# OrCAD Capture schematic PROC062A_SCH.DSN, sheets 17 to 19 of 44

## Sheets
17 16. DDR4 ECC & TERMINATIONS: size C; title: DDR4 ECC & TERMINATIONS
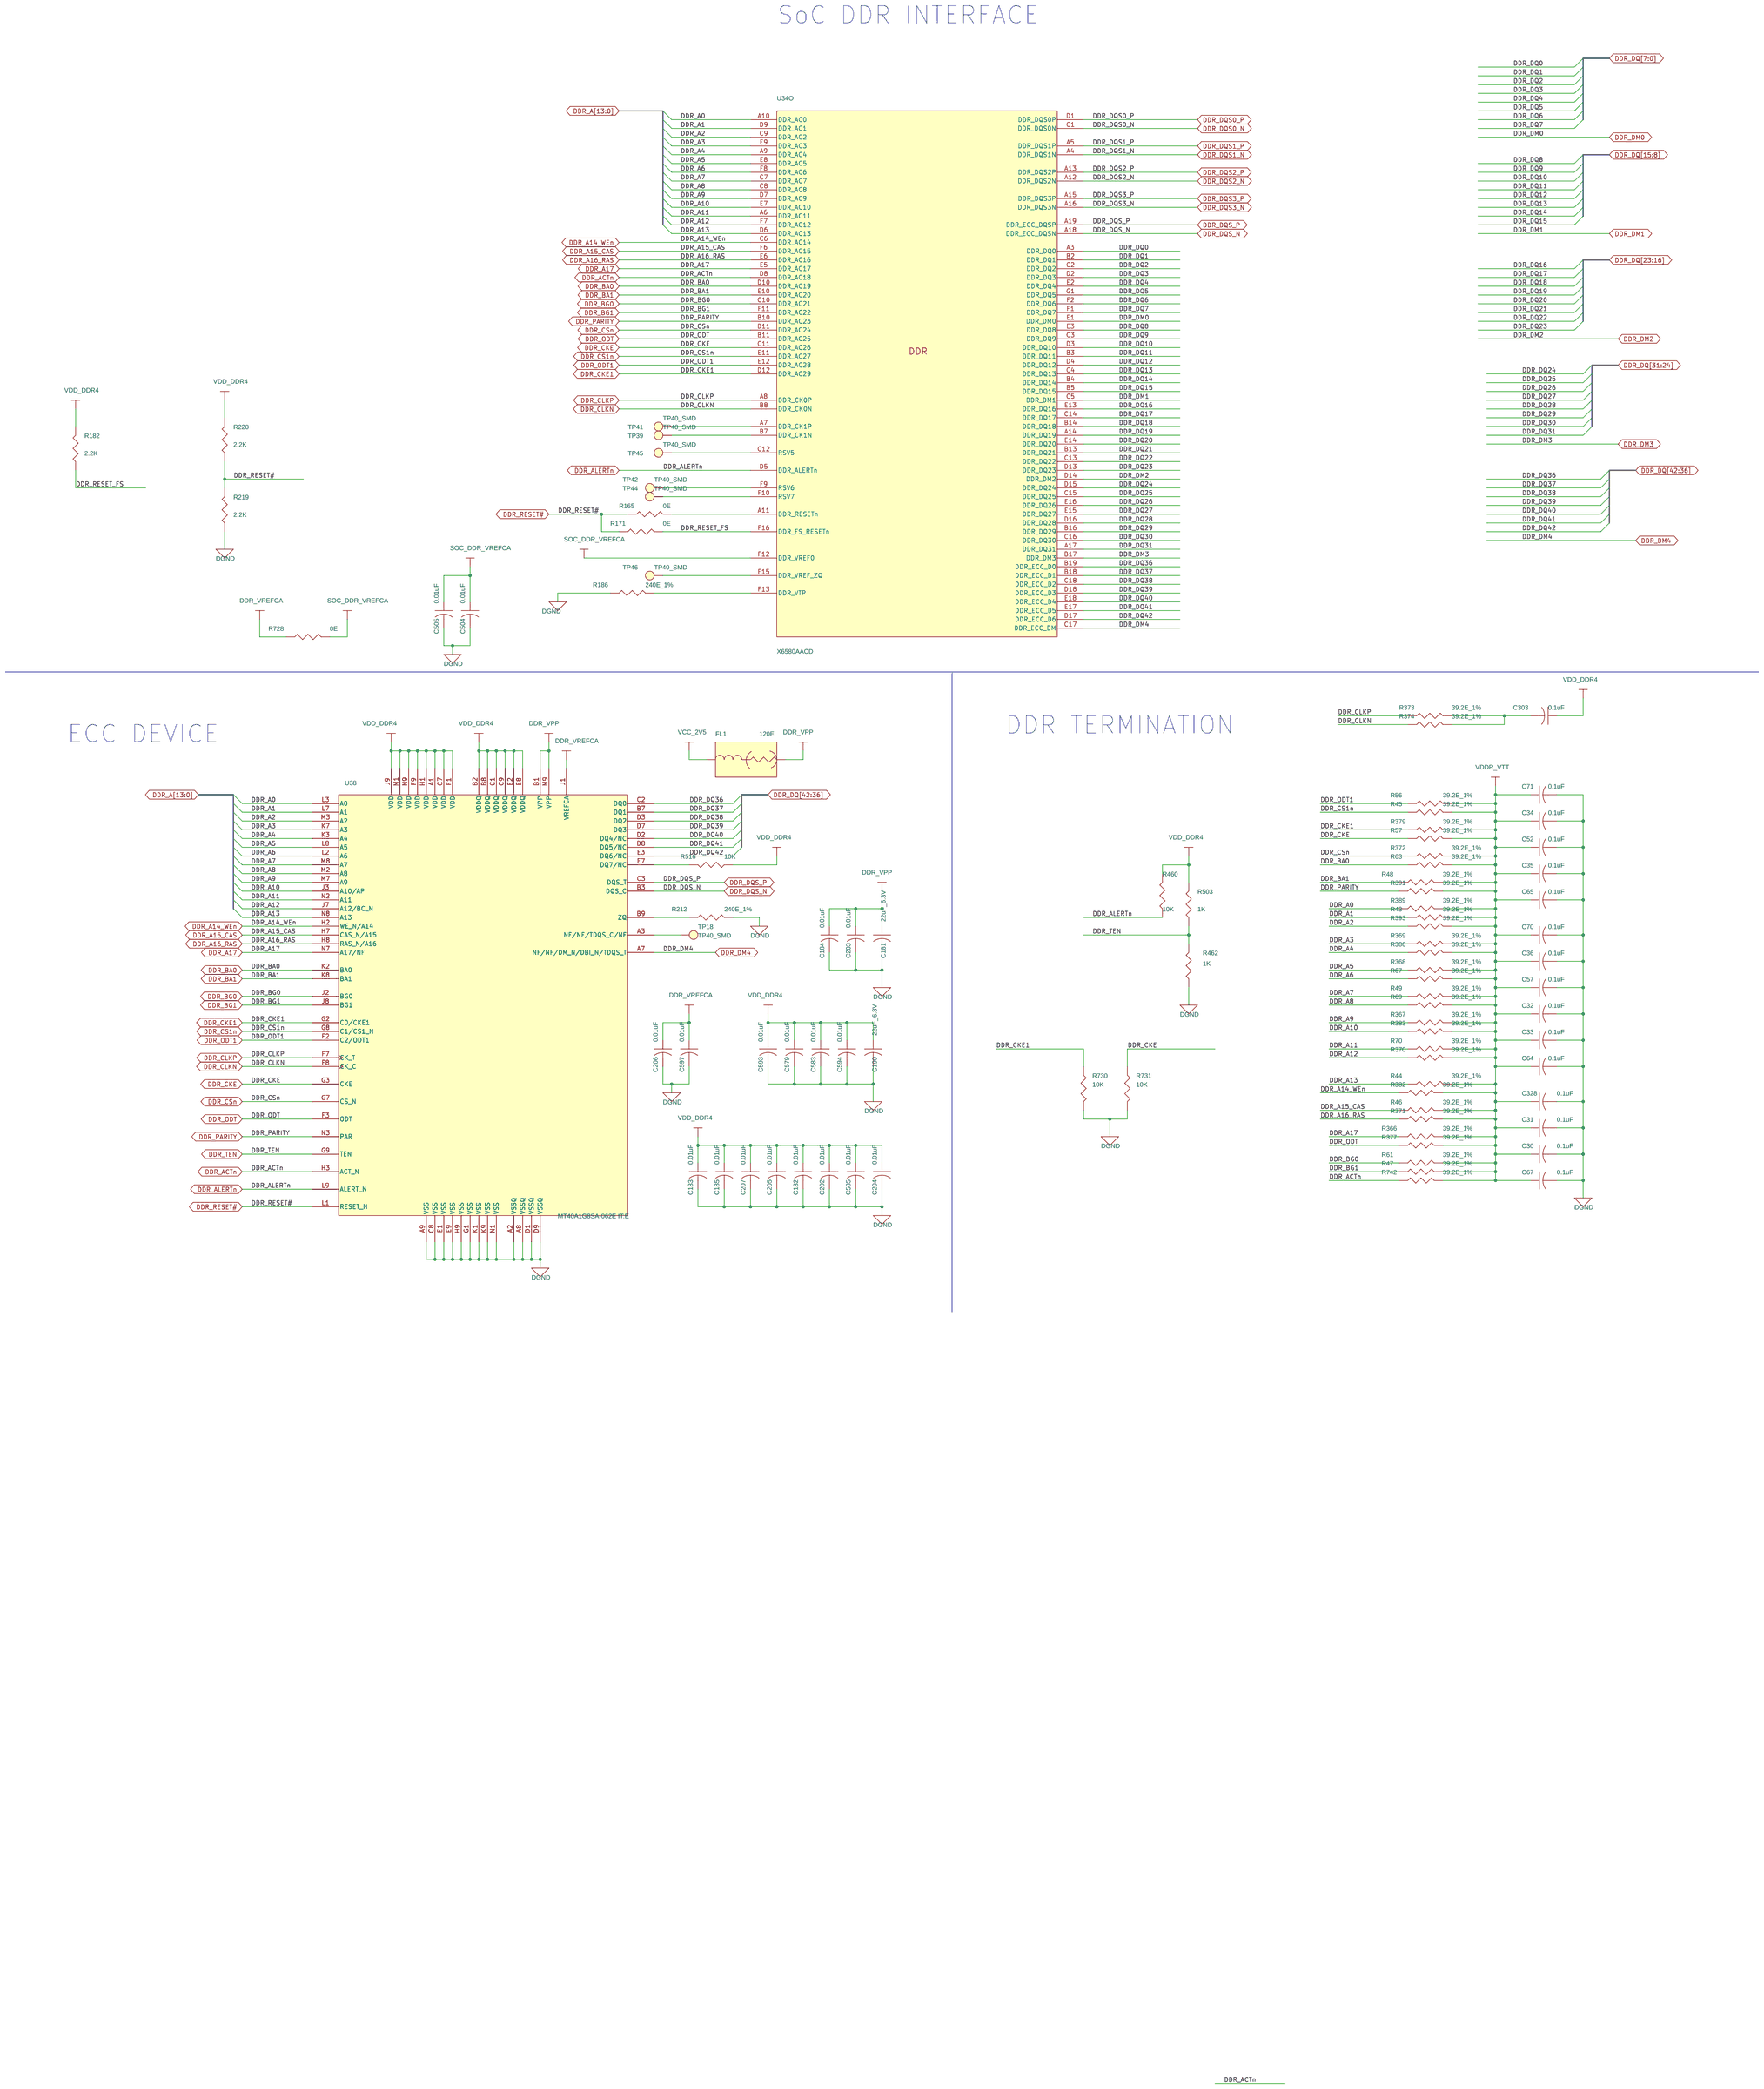
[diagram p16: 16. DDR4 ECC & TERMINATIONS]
18 17. eMMC FLASH: size C; title: eMMC FLASH_SDCARD INTERFACE
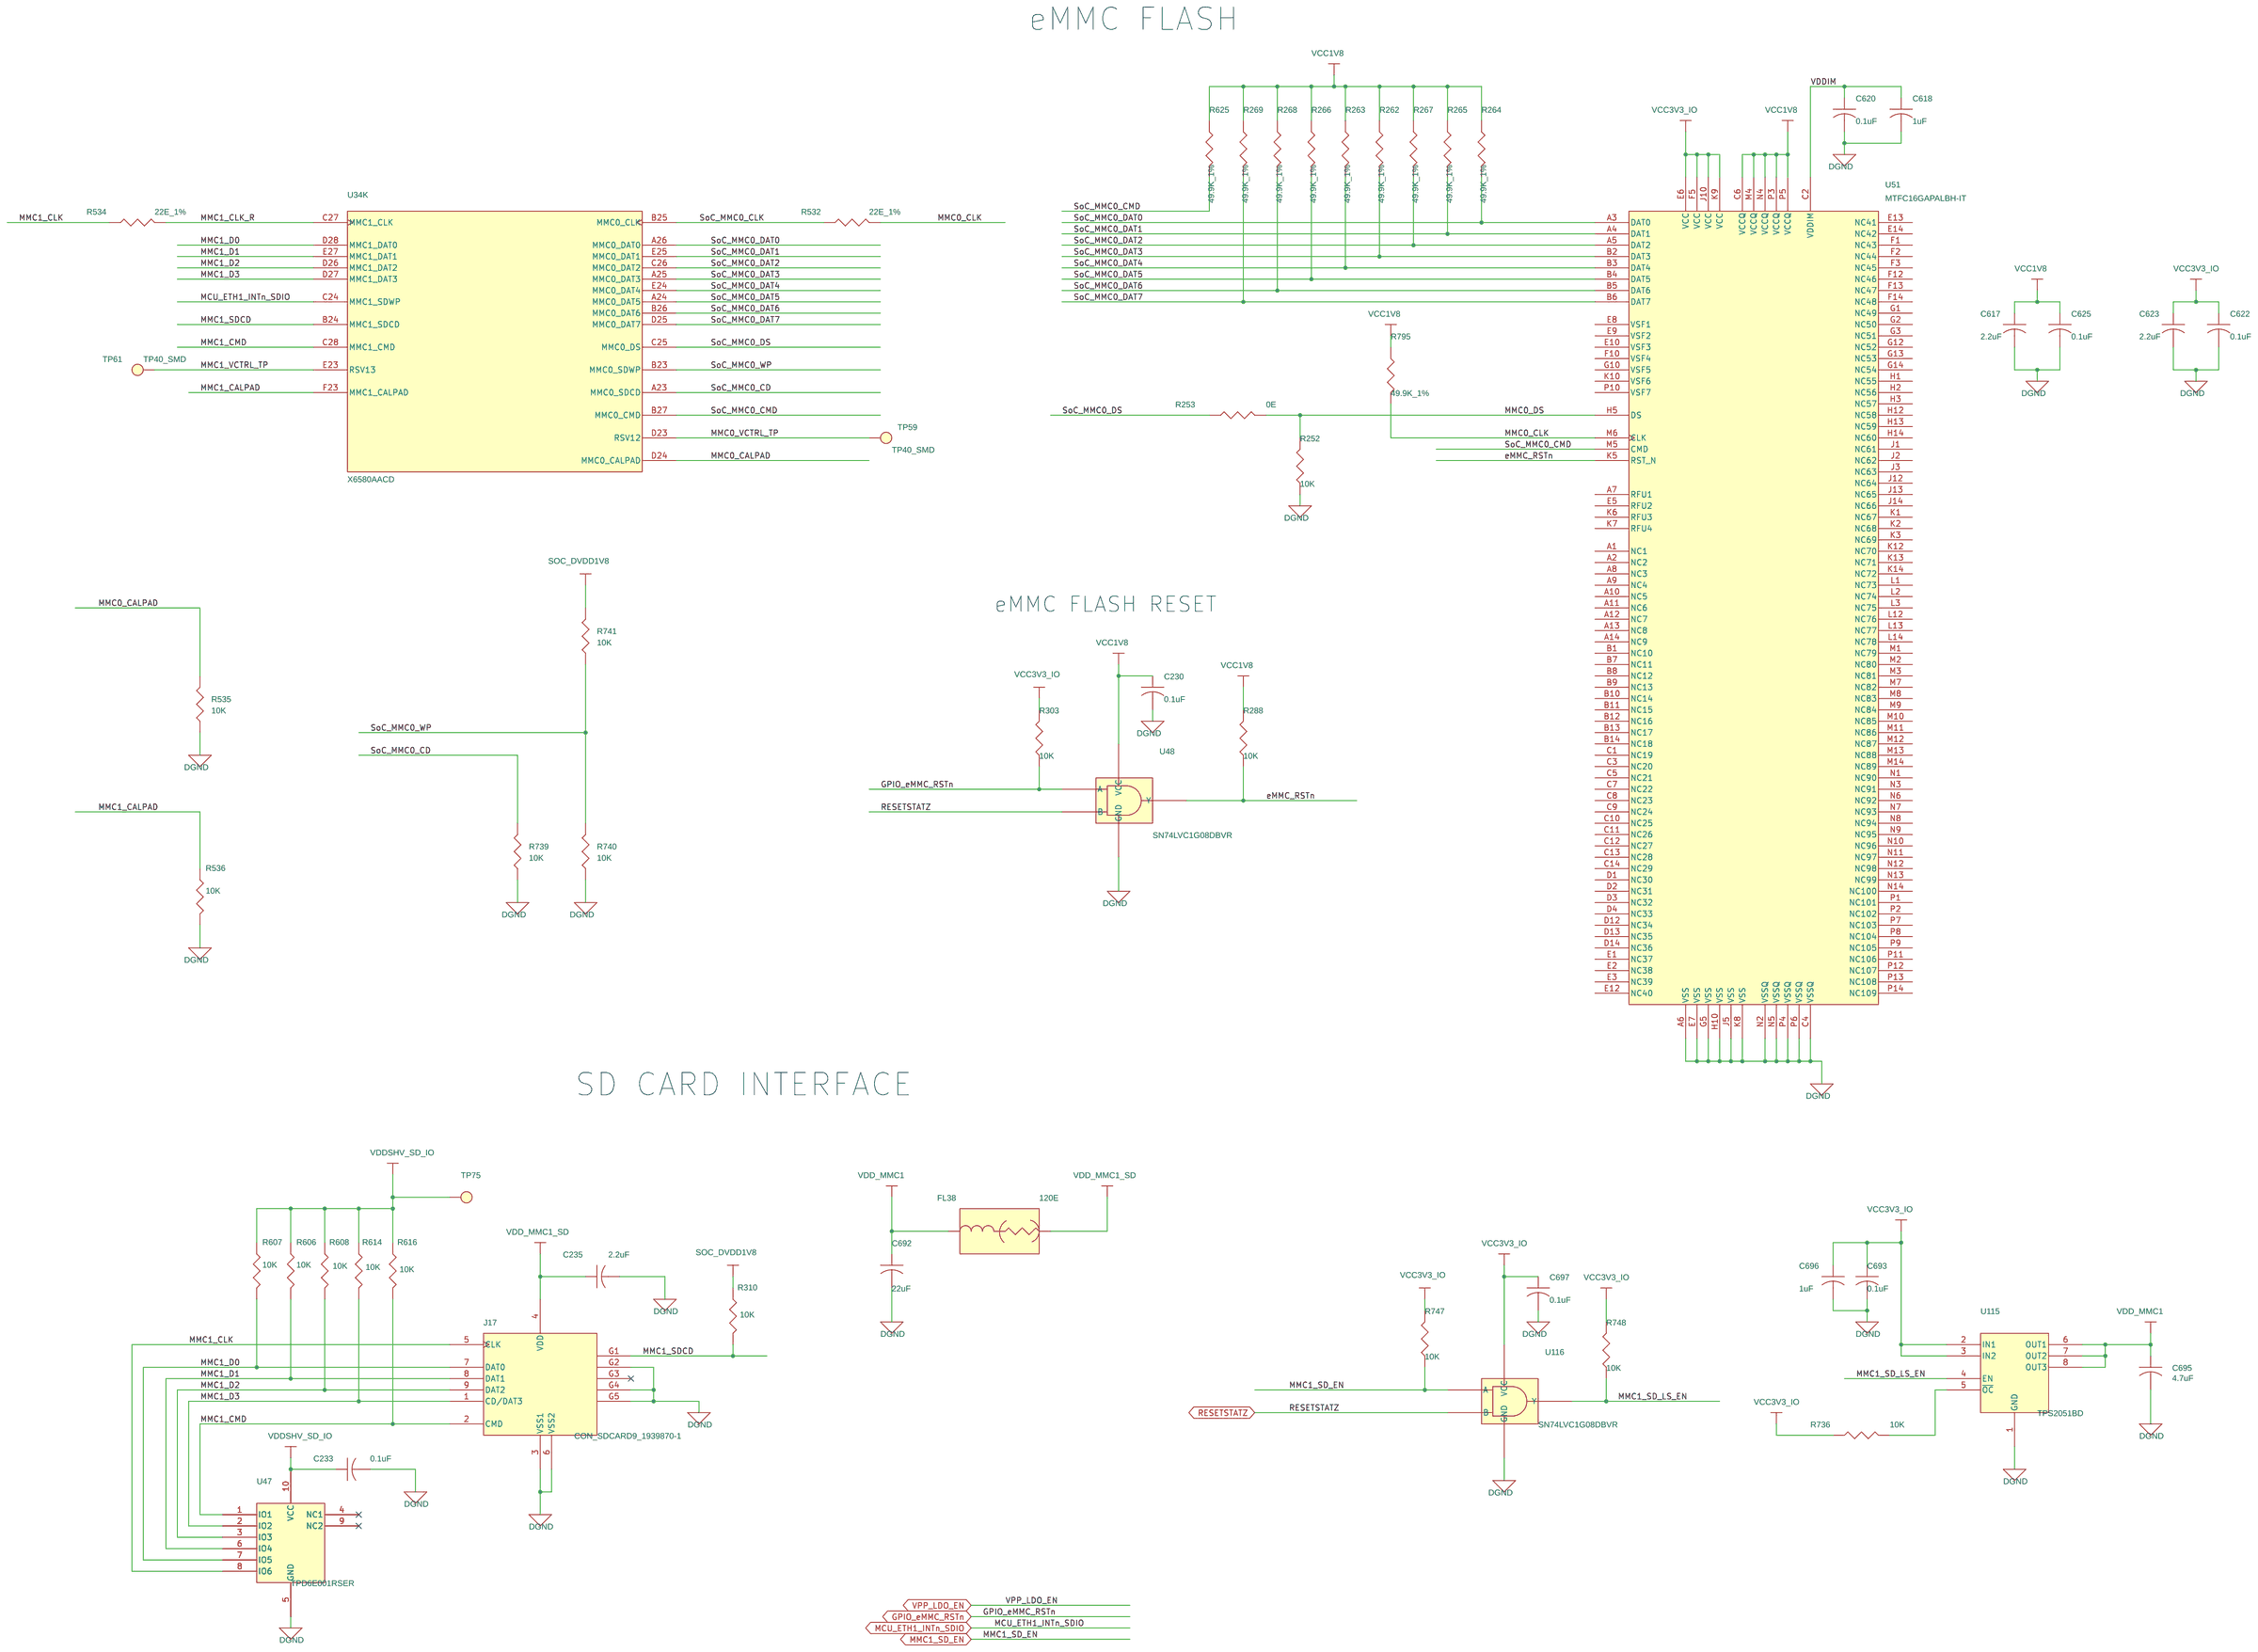
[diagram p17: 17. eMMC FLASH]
19 18. OSPI FLASH & SPI NOR FLASH: size C; title: OSPI FLASH & SPI NOR FLASH

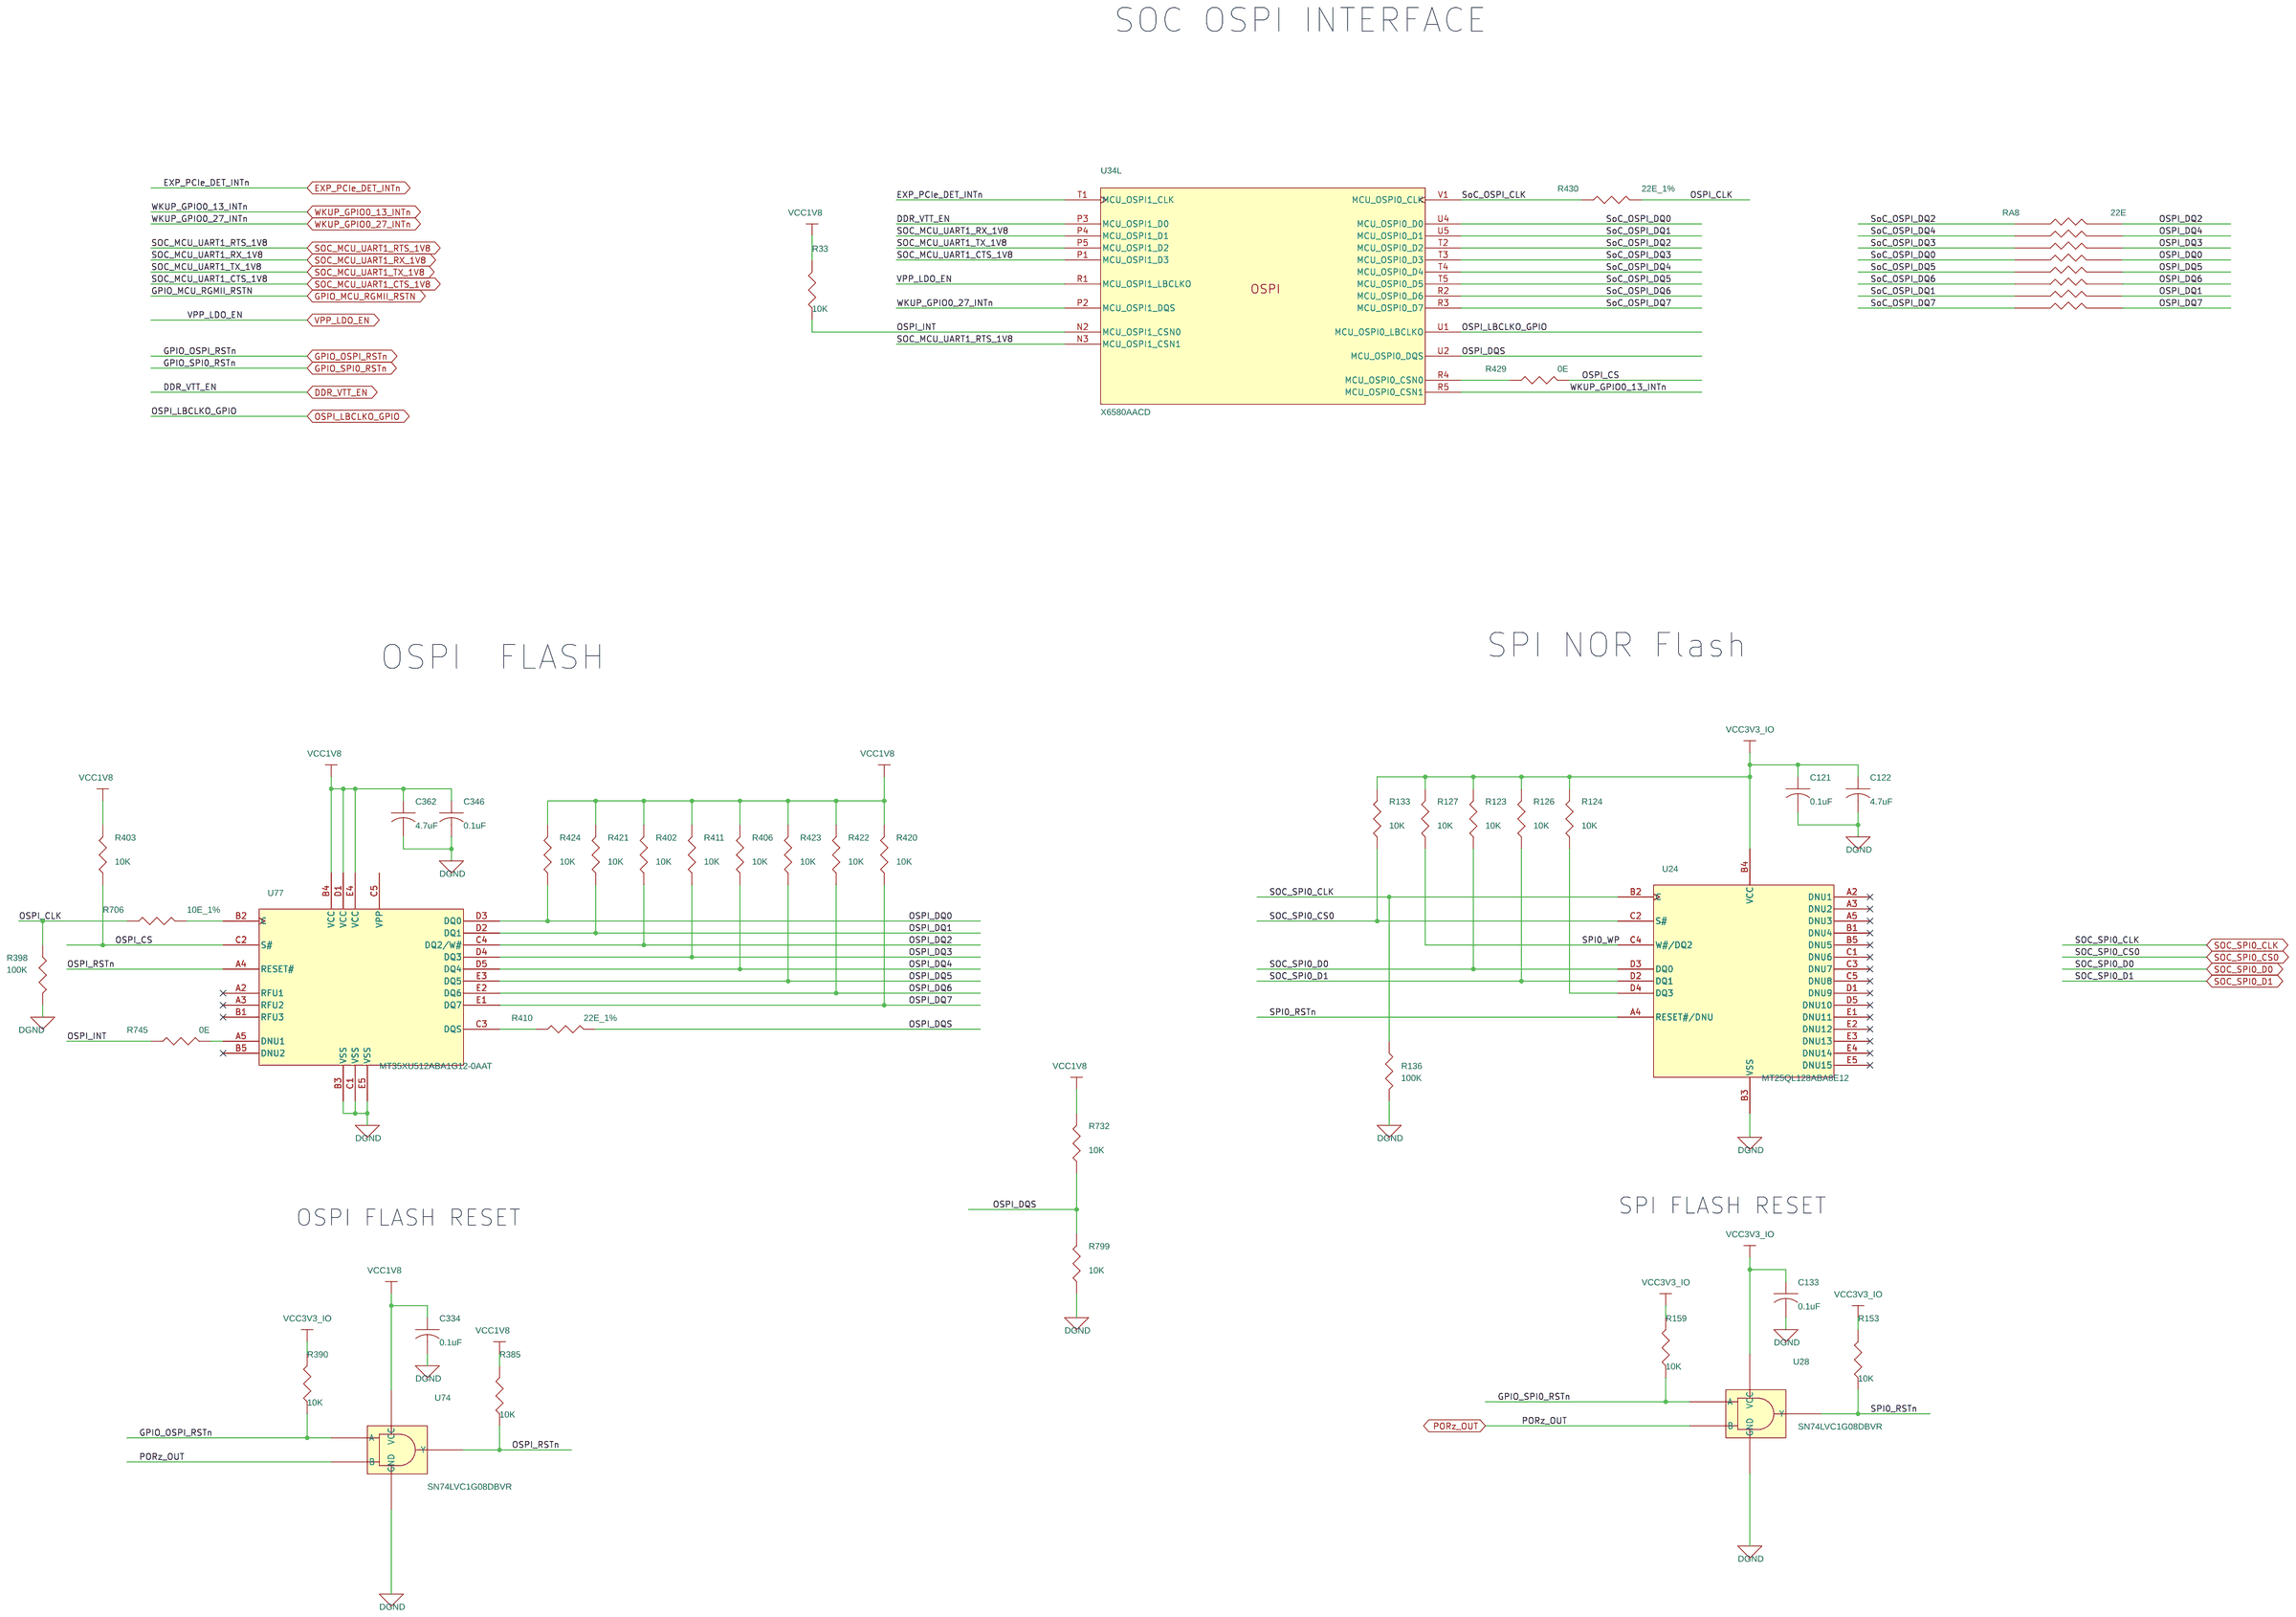
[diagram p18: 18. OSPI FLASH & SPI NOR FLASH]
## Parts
sheet 16. DDR4 ECC & TERMINATIONS
C30  0.1uF  [CAP0201_0-5]
C31  0.1uF  [CAP0201_0-5]
C32  0.1uF  [CAP0201_0-5]
C33  0.1uF  [CAP0201_0-5]
C34  0.1uF  [CAP0201_0-5]
C35  0.1uF  [CAP0201_0-5]
C36  0.1uF  [CAP0201_0-5]
C52  0.1uF  [CAP0201_0-5]
C57  0.1uF  [CAP0201_0-5]
C64  0.1uF  [CAP0201_0-5]
C65  0.1uF  [CAP0201_0-5]
C67  0.1uF  [CAP0201_0-5]
C70  0.1uF  [CAP0201_0-5]
C71  0.1uF  [CAP0201_0-5]
C181  22uF_6.3V  [CAP0603]
C182  0.01uF  [CAP0201_0-5]
C183  0.01uF  [CAP0201_0-5]
C184  0.01uF  [CAP0201_0-5]
C185  0.01uF  [CAP0201_0-5]
C190  22uF_6.3V  [CAP0603]
C202  0.01uF  [CAP0201_0-5]
C203  0.01uF  [CAP0201_0-5]
C204  0.01uF  [CAP0201_0-5]
C205  0.01uF  [CAP0201_0-5]
C206  0.01uF  [CAP0201_0-5]
C207  0.01uF  [CAP0201_0-5]
C303  0.1uF  [CAP0201_0-5]
C328  0.1uF  [CAP0201_0-5]
C504  0.01uF  [CAP0201_0-5]
C505  0.01uF  [CAP0201_0-5]
C579  0.01uF  [CAP0201_0-5]
C583  0.01uF  [CAP0201_0-5]
C585  0.01uF  [CAP0201_0-5]
C593  0.01uF  [CAP0201_0-5]
C594  0.01uF  [CAP0201_0-5]
C597  0.01uF  [CAP0201_0-5]
FL1  120E  [EMIFIL_BLM15A_0402_0-6]
R43  39.2E_1%  [RES0402]
R44  39.2E_1%  [RES0402]
R45  39.2E_1%  [RES0402]
R46  39.2E_1%  [RES0402]
R47  39.2E_1%  [RES0402]
R48  39.2E_1%  [RES0402]
R49  39.2E_1%  [RES0402]
R56  39.2E_1%  [RES0402]
R57  39.2E_1%  [RES0402]
R61  39.2E_1%  [RES0402]
R63  39.2E_1%  [RES0402]
R67  39.2E_1%  [RES0402]
R69  39.2E_1%  [RES0402]
R70  39.2E_1%  [RES0402]
R165  0E  [RES0402_0-5]
R171  0E  [RES0402_0-5]
R182  2.2K  [RES0402_0-5]
R186  240E_1%  [RES0402]
R212  240E_1%  [RES0402]
R219  2.2K  [RES0402_0-5]
R220  2.2K  [RES0402_0-5]
R366  39.2E_1%  [RES0402]
R367  39.2E_1%  [RES0402]
R368  39.2E_1%  [RES0402]
R369  39.2E_1%  [RES0402]
R370  39.2E_1%  [RES0402]
R371  39.2E_1%  [RES0402]
R372  39.2E_1%  [RES0402]
R373  39.2E_1%  [RES0402]
R374  39.2E_1%  [RES0402]
R377  39.2E_1%  [RES0402]
R379  39.2E_1%  [RES0402]
R382  39.2E_1%  [RES0402]
R383  39.2E_1%  [RES0402]
R386  39.2E_1%  [RES0402]
R389  39.2E_1%  [RES0402]
R391  39.2E_1%  [RES0402]
R393  39.2E_1%  [RES0402]
R460  10K  [RES0402_0-5]
R462  1K  [RES0201]
R503  1K  [RES0201]
R516  10K  [RES0402_0-5]
R728  0E  [RES0402_0-5]
R730  10K  [RES0402_0-5]
R731  10K  [RES0402_0-5]
R742  39.2E_1%  [RES0402]
TP18  TP40_SMD  [TP40_SMD]
TP39  TP40_SMD  [TP40_SMD]
TP41  TP40_SMD  [TP40_SMD]
TP42  TP40_SMD  [TP40_SMD]
TP44  TP40_SMD  [TP40_SMD]
TP45  TP40_SMD  [TP40_SMD]
TP46  TP40_SMD  [TP40_SMD]
U38  MT40A1G8SA-062E IT:E  [FBGA78_31-49_300X440_1-2]
sheet 17. eMMC FLASH
C230  0.1uF  [CAP0201_0-5]
C233  0.1uF  [CAP0201_0-5]
C235  2.2uF  [CAP0402_0-75]
C617  2.2uF  [CAP0402_0-75]
C618  1uF  [CAP0402_0-75]
C620  0.1uF  [CAP0201_0-5]
C622  0.1uF  [CAP0201_0-5]
C623  2.2uF  [CAP0402_0-75]
C625  0.1uF  [CAP0201_0-5]
C692  22uF  [CAP1206_2]
C693  0.1uF  [CAP0201_0-5]
C695  4.7uF  [CAP0402_0-75]
C696  1uF  [CAP0402_0-75]
C697  0.1uF  [CAP0201_0-5]
FL38  120E  [EMIFIL_BLM15A_0402_0-6]
J17  CON_SDCARD9_1939870-1  [CON_SD9_1939870-1_S_R_S_2-9]
R252  10K  [RES0402_0-5]
R253  0E  [RES0402_0-5]
R262  49.9K_1%  [RES0402]
R263  49.9K_1%  [RES0402]
R264  49.9K_1%  [RES0402]
R265  49.9K_1%  [RES0402]
R266  49.9K_1%  [RES0402]
R267  49.9K_1%  [RES0402]
R268  49.9K_1%  [RES0402]
R269  49.9K_1%  [RES0402]
R288  10K  [RES0402_0-5]
R303  10K  [RES0402_0-5]
R310  10K  [RES0402_0-5]
R532  22E_1%  [RES0402]
R534  22E_1%  [RES0402]
R535  10K  [RES0402_0-5]
R536  10K  [RES0402_0-5]
R606  10K  [RES0402_0-5]
R607  10K  [RES0402_0-5]
R608  10K  [RES0402_0-5]
R614  10K  [RES0402_0-5]
R616  10K  [RES0402_0-5]
R625  49.9K_1%  [RES0402]
R736  10K  [RES0402_0-5]
R739  10K  [RES0402_0-5]
R740  10K  [RES0402_0-5]
R741  10K  [RES0402_0-5]
R747  10K  [RES0402_0-5]
R748  10K  [RES0402_0-5]
R795  49.9K_1%  [RES0402]
TP59  TP40_SMD  [TP40_SMD]
TP61  TP40_SMD  [TP40_SMD]
TP75  TP40_SMD  [TP40_SMD]
U47  TPD6E001RSER  [UQFN10_19-68_80X60_0-6]
U48  SN74LVC1G08DBVR  [SOT23-5]
U51  MTFC16GAPALBH-IT  [VFBGA153_19-68_460X520_1-1]
U115  TPS2051BD  [SOIC8_1-8]
U116  SN74LVC1G08DBVR  [SOT23-5]
sheet 18. OSPI FLASH & SPI NOR FLASH
C121  0.1uF  [CAP0201_0-5]
C122  4.7uF  [CAP0402_0-75]
C133  0.1uF  [CAP0201_0-5]
C334  0.1uF  [CAP0201_0-5]
C346  0.1uF  [CAP0201_0-5]
C362  4.7uF  [CAP0402_0-75]
R33  10K  [RES0402_0-5]
R123  10K  [RES0402_0-5]
R124  10K  [RES0402_0-5]
R126  10K  [RES0402_0-5]
R127  10K  [RES0402_0-5]
R133  10K  [RES0402_0-5]
R136  100K  [RES0402_0-5]
R153  10K  [RES0402_0-5]
R159  10K  [RES0402_0-5]
R385  10K  [RES0402_0-5]
R390  10K  [RES0402_0-5]
R398  100K  [RES0402_0-5]
R402  10K  [RES0402_0-5]
R403  10K  [RES0402_0-5]
R406  10K  [RES0402_0-5]
R410  22E_1%  [RES0402]
R411  10K  [RES0402_0-5]
R420  10K  [RES0402_0-5]
R421  10K  [RES0402_0-5]
R422  10K  [RES0402_0-5]
R423  10K  [RES0402_0-5]
R424  10K  [RES0402_0-5]
R429  0E  [RES0402_0-5]
R430  22E_1%  [RES0402]
R706  10E_1%  [RES0402_0-5]
R732  10K  [RES0402_0-5]
R745  0E  [RES0402_0-5]
R799  10K  [RES0402_0-5]
RA8  22E  [RESA_0402-8]
U24  MT25QL128ABA8E12  [TPBGA24_39-37_240X320_1-2]
U28  SN74LVC1G08DBVR  [SOT23-5]
U74  SN74LVC1G08DBVR  [SOT23-5]
U77  MT35XU512ABA1G12-0AAT  [TPBGA24_39-37_240X320_1-2]
sheet 29. USB2.0_INTERFACE
U34  X6580AACD  [BGA784_31-49_910X910_1-7]  (sections A,B,C,D,E,F,G,H,I,J,K,L,M,N,O,P,Q,R,S)

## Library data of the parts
C30-C36 C52 C57 C64 C65 C67 C70 C71 C121 C133 C230 C233 C303 C328 C334 C346 C620 C622 C625 C693 C697 = CAP: CAP CERAMIC 0.1uF 16V 10% X5R 0201; Chkd/date: MANIRAJA/120218; Crtd /date: MANIRAJA/120218; Custom_Duty: 15%; Customs_HS_Code: 85322990; Distributor_name: DIGIKEY; Distributor_part_number: 490-16742-1-ND; Height: 0.33MM; Mfr_name: MURATA; Mfr_part_number: GRM033R61C104KE84J; Mistral Part No: 120009030072-R; Package: 0201; Part_type: CAPACITORS\CERAMIC; Project: TI_MAXIE_CPB; RoHS: RoHS; Temperature: -55°C+85°C; Tolerance: 10%; Voltage: 16V; Wattage: NA; Weight: 0.33mg; Datasheet: Y:\MIS_DATABASE\DATASHEETS\CAPACITORS\GRM033R61C104KE84.PDF
C181 C190 = CAP: CAP CERAMIC 22uF 6.3V 20% X5R 0603; Alternate_mfr_name_A: YAGEO AMERICA; Alternate_mfr_part_number_A: CC0603MRX5R5BB226; Chkd/date: JEBRAN/090915; Crtd /date: JEBRAN/090915; Custom_Duty: 15%; Customs_HS_Code: 85322990; Distributor_name: DIGIKEY; Distributor_name_A: DIGIKEY; Distributor_part_number: 490-7611-2-ND; Distributor_part_number_A: 311-1815-1-ND; Height: 1.00MM; Mfr_name: MURATA; Mfr_part_number: GRM188R60J226MEA0; Mistral Part No: 120015090007-R; Package: 0603; Part_type: CAPACITORS\CERAMIC; Project: OCTBTS_3000; RoHS: RoHS; Temperature: -55°C+85°C; Tolerance: 20%; Voltage: 6.3V; Wattage: NA; Weight: NA; Datasheet: Y:\MIS_DATABASE\DATASHEETS\CAPACITORS\GRM188SERIES.PDF
C182-C185 C202-C207 C504 C505 C579 C583 C585 C593 C594 C597 = CAP: CAP CERAMIC 0.01uF 25V 10% X5R 0201; Chkd/date: MANIRAJA/230118; Crtd /date: MANIRAJA/230118; Custom_Duty: 15%; Customs_HS_Code: 85322990; Distributor_name: DIGIKEY; Distributor_part_number: GRM033R61E103KA12J-ND; Height: 0.33MM; Mfr_name: MURATA; Mfr_part_number: GRM033R61E103KA12J; Mistral Part No: 120018010007-R; Package: 0201; Part_type: CAPACITORS\CERAMIC; Project: TI_MAXIE_CPB; RoHS: RoHS; Temperature: -55°C+85°C; Tolerance: 10%; Voltage: 25V; Wattage: NA; Weight: 0.33mg; Datasheet: Y:\MIS_DATABASE\DATASHEETS\CAPACITORS\GRM033R61E103KA12.PDF
FL1 FL38 = EMIFILTER_IND: FERRITE CHIP 120E 1.3A 0402; Chkd/date: VASANTHA/010117; Crtd /date: CHAITHANYA/150312; Custom_Duty: 24%; Customs_HS_Code: 85437099; Distributor_name: DIGIKEY; Distributor_part_number: 490-5203-1-ND; Footprint Path: Y:\MIS_DATABASE\Library\ALTIUM_TOOL\PCB_FOOTPRINTS\Altium_Footprint_Lib.PcbLib; Height: 0.55MM; Library Path: Y:\MIS_DATABASE\Library\ALTIUM_TOOL\SCHEMATICS_PARTS\MS_FILTER_Library.schlib; Mfr_name: MURATA; Mfr_part_number: BLM15PD121SN1; Mistral Part No: 130012030043-R; Package: 0402; Part_type: MISC\FILTER; Project: GEN_3-8; RoHS: RoHS; Temperature: -55°C+125°C; Tolerance: 25%; Voltage: NA; Wattage: NA; Weight: 0.65mg; Datasheet: Y:\MIS_DATABASE\DATASHEETS\DISCRETES\INDUCTORS\BLM18K-SERIES.PDF
R43-R49 R56 R57 R61 R63 R67 R69 R70 R366-R374 R377 R379 R382 R383 R386 R389 R391 R393 R742 = RESISTOR: RES 39.2E 1/16W 1% 0402; Chkd/date: RAGESH/210411; Crtd /date: MAZHAR/210411; Custom_Duty: 15%; Customs_HS_Code: 85332119; Distributor_name: DIGIKEY; Distributor_part_number: RMCF0402FT39R2CT-ND; Height: 0.40MM; Mfr_name: STACKPOLE ELECTRONICS; Mfr_part_number: RMCF0402FT39R2; Mistral Part No: 110011040030-R; Package: 0402; Part_type: RESISTORS\FIXED; Project: AOD_POD-BASECARD; RoHS: RoHS; Temperature: -55°C+155°C; Tolerance: 1%; Voltage: NA; Wattage: 1/16W; Weight: NA; Datasheet: Y:\MIS_DATABASE\DATASHEETS\RESISTORS\RMCF-SERIES.PDF
R165 R171 R253 R429 R728 R745 = RESISTOR: RES 0E 1/16W 0402; Chkd/date: VASANTHA/201216; Crtd /date: MUDDU/190810; Custom_Duty: 15%; Customs_HS_Code: 85332119; Distributor_name: DIGIKEY; Distributor_part_number: 541-0.0JCT-ND; Footprint Path: Y:\MIS_DATABASE\Library\ALTIUM_TOOL\PCB_FOOTPRINTS\Altium_Footprint_Lib.PcbLib; Height: 0.40MM; Library Path: Y:\MIS_DATABASE\Library\ALTIUM_TOOL\SCHEMATICS_PARTS\MS_DISCRETE_Library.schlib; Mfr_name: VISHAY; Mfr_part_number: CRCW04020000Z0ED; Mistral Part No: 110010080019-P; Package: 0402; Part_type: RESISTORS\FIXED; Project: PB_BUGBASE; RoHS: Pb-Free; Temperature: -55°C+155°C; Tolerance: NA; Voltage: NA; Wattage: 1/16W; Weight: 0.65g/1000pcs; Datasheet: Y:\MIS_DATABASE\DATASHEETS\RESISTORS\CRCW0603.PDF
R182 R219 R220 = RESISTOR: RES 2.2K 1/16W 5% 0402; Chkd/date: VASANTHA/061216; Crtd /date: BAVISH/021210; Custom_Duty: 15%; Customs_HS_Code: 85332119; Distributor_name: DIGIKEY; Distributor_part_number: 311-2.2KJRCT-ND; Footprint Path: VALUE IS VAILABLE 3 TIMES; Height: 0.40MM; Mfr_name: YAGEO AMERICA; Mfr_part_number: RC0402JR-072K2L; Mistral Part No: 110010120018-R; Package: 0402; Part_type: RESISTORS\FIXED; Project: TE4; RoHS: RoHS; Temperature: -55°C+155°C; Tolerance: 5%; Voltage: NA; Wattage: 1/16W; Weight: 0.65mg; Datasheet: Y:\MIS_DATABASE\DATASHEETS\RESISTORS\YAGEO.PDF
R186 R212 = RESISTOR: RES 240E 1/10W 1% 0402; Chkd/date: MAZHAR/150611; Crtd /date: BAVISH/020611; Custom_Duty: 15%; Customs_HS_Code: 85332119; Distributor_name: DIGIKEY; Distributor_part_number: P240LCT-ND; Height: 0.40MM; Mfr_name: PANASONIC-ECG; Mfr_part_number: ERJ-2RKF2400X; Mistral Part No: 110011060017-R; Package: 0402; Part_type: RESISTORS\FIXED; Project: AM4515_EVM_LCD; RoHS: RoHS; Temperature: -55°C+125°C; Tolerance: 1%; Voltage: NA; Wattage: 1/10W; Weight: 0.8/1000g; Datasheet: Y:\MIS_DATABASE\DATASHEETS\RESISTORS\ERJ-2R.PDF
R33 R123 R124 R126 R127 R133 R153 R159 R252 R288 R303 R310 R385 R390 R402 R403 R406 R411 R420-R424 R460 R516 R535 R536 R606-R608 R614 R616 R730-R732 R736 R739-R741 R747 R748 R799 = RESISTOR: RES 10K 1/16W 5% 0402; Chkd/date: VASANTHA/061216; Crtd /date: MAZHAR/230805; Custom_Duty: 15%; Customs_HS_Code: 85332119; Distributor_name: DIGIKEY; Distributor_part_number: 311-10KJRCT-ND; Footprint Path: Y:\MIS_DATABASE\Library\ALTIUM_TOOL\PCB_FOOTPRINTS\Altium_Footprint_Lib.PcbLib; Height: 0.40MM; Library Path: Y:\MIS_DATABASE\Library\ALTIUM_TOOL\SCHEMATICS_PARTS\MS_DISCRETE_Library.schlib; Mfr_name: YAGEO AMERICA; Mfr_part_number: RC0402JR-0710KL; Mistral Part No: 110009030208-R; Package: 0402; Part_type: RESISTORS\FIXED; Project: HSE; RoHS: Pb-Free; Temperature: -55°C+155°C; Tolerance: 5%; Voltage: NA; Wattage: 1/16W; Weight: 0.65mg; Datasheet: Y:\MIS_DATABASE\DATASHEETS\RESISTORS\YAGEO-RC0402.PDF
R462 R503 = RESISTOR: RES 1K 1/20W 5% 0201; Chkd/date: JEBRAN/110815; Crtd /date: JEBRAN/110815; Custom_Duty: 15%; Customs_HS_Code: 85332119; Distributor_name: DIGIKEY; Distributor_part_number: 541-1.00KAABCT-ND; Height: 0.28MM; Mfr_name: VISHAY; Mfr_part_number: CRCW02011K00FKED; Mistral Part No: 110015080014-R; Package: 0201; Part_type: RESISTORS\FIXED; Project: OCTASIC_3000; RoHS: RoHS; Temperature: -55°C+155°C; Tolerance: 5%; Voltage: NA; Wattage: 1/20W; Weight: NA; Datasheet: Y:\MIS_DATABASE\DATASHEETS\RESISTORS\CRCW0201.PDF
TP18 TP39 TP41 TP42 TP44-TP46 TP59 TP61 TP75 = TESTPOINT: TESTPOINT CIR 40 SMD; Chkd/date: MAZHAR/190505; Crtd /date: MAZHAR/190505; Distributor_name: NA; Distributor_part_number: NA; Footprint Path: Y:\MIS_DATABASE\Library\ALTIUM_TOOL\PCB_FOOTPRINTS\Altium_Footprint_Lib.PcbLib; Height: NA; Library Path: Y:\MIS_DATABASE\Library\ALTIUM_TOOL\SCHEMATICS_PARTS\MS_DISCRETE_Library.schlib; MECHANICAL 3D STEP FILE: NA; Mfr_name: LOCAL; Mistral Part No: 130009030933; Package: SMD; Project: RAINIER-3; RoHS: NA; Temperature: NA; Tolerance: NA; Voltage: NA; Wattage: NA; Weight: NA; Datasheet: NA
U38 = MT40A1G8WE-083_FBGA78: IC 1G8 DDR4 SDRAM MEMORY FBGA78; Chkd/date: MANIRAJA/010819; Crtd /date: ALVY/010819; Custom_Duty: 15%; Customs_HS_Code: 85423100; Distributor_name: DIGIKEY; Distributor_part_number: MT40A1G8SA-062EIT:E-ND; Footprint Path: Y:\MIS_DATABASE\Library\ALTIUM_TOOL\PCB_FOOTPRINTS\Altium_Footprint_Lib.PcbLib; Height: 1.20MM; Library Path: Y:\MIS_DATABASE\Library\ALTIUM_TOOL\SCHEMATICS_PARTS\MS_MISCMEMORY_Library.schlib; Mfr_name: MICRON; Mistral Part No: 141119080001-R; Package: FBGA78; Part_type: ICS\DIGITAL\MEMORY; Project: TI_MAXIE_CPB; RoHS: RoHS; Temperature: -40°C+95°C; Tolerance: NA; Voltage: NA; Wattage: NA; Weight: NA; Datasheet: Y:\MIS_DATABASE\DATASHEETS\ICS\MEMORY\MT40AXX.PDF
C235 C617 C623 = CAP: CAP CERAMIC 2.2uF 10V 20% X5R 0402; Chkd/date: MANIRAJA/240118; Crtd /date: MANIRAJA/240118; Custom_Duty: 15%; Customs_HS_Code: 85322990; Distributor_name: DIGIKEY; Distributor_part_number: 490-12254-1-ND; Height: 0.55MM; Mfr_name: MURATA; Mfr_part_number: GRT155R61A225ME01D; Mistral Part No: 120018010016-R; Package: 0402; Part_type: CAPACITORS\CERAMIC; Project: TI_MAXIE_CPB; RoHS: RoHS; Temperature: -55°C+85°C; Tolerance: 20%; Voltage: 10V; Wattage: NA; Weight: 0.65mg; Datasheet: Y:\MIS_DATABASE\DATASHEETS\CAPACITORS\GRT155R61A225ME01.PDF
C618 C696 = CAP: CAP CERAMIC 1uF 16V 20% X5R 0402; Chkd/date: MANIRAJA/150218; Crtd /date: ALVY/150218; Custom_Duty: 15%; Customs_HS_Code: 85322990; Distributor_name: DIGIKEY; Distributor_part_number: 587-5514-1-ND; Footprint Path: Y:\MIS_DATABASE\Library\ALTIUM_TOOL\PCB_FOOTPRINTS\Altium_Footprint_Lib.PcbLib; Height: 0.55MM; Library Path: Y:\MIS_DATABASE\Library\ALTIUM_TOOL\SCHEMATICS_PARTS\MS_DISCRETE_Library.schlib; Mfr_name: TAIYO YUDEN; Mfr_part_number: EMK105BJ105MV-F; Mistral Part No: 120018020006-R; Package: 0402; Part_type: CAPACITORS\CERAMIC; Project: TI_MAXIE_CPB; RoHS: RoHS; Temperature: -55°C+85°C; Tolerance: 20%; Voltage: 16V; Wattage: NA; Weight: 0.65mg; Datasheet: Y:\MIS_DATABASE\DATASHEETS\CAPACITORS\EMK105BJ105MV-F.PDF
C692 = CAP: CAP CERAMIC 22uF 16V 20% X7R 1206; Chkd/date: VASANTHA/170117; Crtd /date: VASANTHA/170117; Custom_Duty: 15%; Customs_HS_Code: 85322990; Distributor_name: DIGIKEY; Distributor_part_number: 587-4319-1-ND; Height: 1.90MM; Mfr_name: TAIYO YUDEN; Mfr_part_number: EMK316BB7226ML-T; Mistral Part No: 120017010003-R; Package: 1206; Part_type: CAPACITORS\CERAMIC; Project: TRMM_SMART-M_PS; RoHS: RoHS; Temperature: -55°C+125°C; Tolerance: 20%; Voltage: 16V; Wattage: NA; Weight: 16.2mg; Datasheet: Y:\MIS_DATABASE\DATASHEETS\CAPACITORS\EMK316BB7226ML.PDF
C122 C362 C695 = CAP: CAP CERAMIC 4.7uF 10V 20% X5R 0402; Chkd/date: MANIRAJA/230118; Crtd /date: MANIRAJA/230118; Custom_Duty: 15%; Customs_HS_Code: 85322990; Distributor_name: DIGIKEY; Distributor_part_number: 478-10791-1-ND; Height: 0.71MM; Mfr_name: AVX CORPORATION; Mfr_part_number: 0402ZD475MAT2A; Mistral Part No: 120012060002-R; Package: 0402; Part_type: CAPACITORS\CERAMIC; Project: TI_MAXIE_CPB; RoHS: RoHS; Temperature: -55°C+85°C; Tolerance: 20%; Voltage: 10V; Wattage: NA; Weight: 0.65mg; Datasheet: Y:\MIS_DATABASE\DATASHEETS\CAPACITORS\AVX_MLC.PDF
J17 = CON_SDCARD9_1939870-1: CON SD CARD PUSH-PUSH 9POS RT SMD; Chkd/date: MANIRAJA/051017; Crtd /date: MANIRAJA/051017; Custom_Duty: 24%; Customs_HS_Code: 85369090; Distributor_name: DIGIKEY; Distributor_part_number: A118090CT-ND; Height: 2.90MM; MECHANICAL 3D STEP FILE: CON_SD9_1939870-1_S_R_S_3-4; Mfr_name: TE CONNECTIVITY; Mfr_part_number: 1939870-1; Mistral Part No: 150017100004-R; Package: SMD; Part_type: CONNECTOR\MEMORY CARD; Project: TI_MAXIE_CPB; RoHS: RoHS; Temperature: NA; Tolerance: NA; Voltage: NA; Wattage: NA; Weight: NA; Datasheet: Y:\MIS_DATABASE\DATASHEETS\CONNECTORS\1939870-XX.PDF
R262-R269 R625 R795 = RESISTOR: RES 49.9K1/16W 1% 0402; Chkd/date: MAZHAR/220709; Crtd /date: GEETHA/090606; Custom_Duty: 15%; Customs_HS_Code: 85332119; Distributor_name: DIGIKEY; Distributor_part_number: 311-49.9KLRCT-ND; Height: 0.40MM; Mfr_name: YAGEO AMERICA; Mfr_part_number: RC0402FR-0749K9L; Mistral Part No: 110009030904-P; Package: 0402; Part_type: RESISTORS\FIXED; Project: PNAV; RoHS: Pb-Free; Tolerance: 1%; Wattage: 1/16W; Datasheet: Y:\MIS_DATABASE\DATASHEETS\RESISTORS\YAGEO-RC0402.PDF
R410 R430 R532 = RESISTOR: RES 22E 1/16W 1% 0402; Alternate_mfr_name_A: VISHAY; Alternate_mfr_part_number_A: CRCW040222R0FKED; Chkd/date: SUHAS/290910; Crtd /date: MAZHAR/090909; Cust_part_number: 4700-80047E; Custom_Duty: 15%; Customs_HS_Code: 85332119; Distributor_name: DIGIKEY; Distributor_name_A: DIGIKEY; Distributor_part_number: 311-22.0LRCT-ND; Distributor_part_number_A: 541-22.0LCT-ND; Height: 0.40MM; Mfr_name: YAGEO AMERICA; Mfr_part_number: RC0402FR-0722RL; Mistral Part No: 110009090004-P; Package: 0402; Part_type: RESISTORS\FIXED; Project: VMEFMCD; Remarks: In alternate datasheet it is RoHS COMPLIANT. Y:\MIS_DATABASE\DATASHEETS\RESISTORS\CRCW0402.PDF; RoHS: Pb-Free; SIGNAL_MODEL: RESISTOR_RES0402_22E_22E; Temperature: -55°C+155°C; Tolerance: 1%; Voltage: 50V; Wattage: 1/16W; Weight: 0.8g/1000pcs; Datasheet: Y:\MIS_DATABASE\DATASHEETS\RESISTORS\YAGEO-RC0402.PDF
R534 = RESISTOR: RES 22E 1/16W 1% 0402; Alternate_mfr_name_A: VISHAY; Alternate_mfr_part_number_A: CRCW040222R0FKED; Chkd/date: SUHAS/290910; Crtd /date: MAZHAR/090909; Cust_part_number: 4700-80047E; Custom_Duty: 15%; Customs_HS_Code: 85332119; Distributor_name: DIGIKEY; Distributor_name_A: DIGIKEY; Distributor_part_number: 311-22.0LRCT-ND; Distributor_part_number_A: 541-22.0LCT-ND; Height: 0.40MM; Mfr_name: YAGEO AMERICA; Mfr_part_number: RC0402FR-0722RL; Mistral Part No: 110009090004-P; Package: 0402; Part_type: RESISTORS\FIXED; Project: VMEFMCD; Remarks: In alternate datasheet it is RoHS COMPLIANT. Y:\MIS_DATABASE\DATASHEETS\RESISTORS\CRCW0402.PDF; RoHS: Pb-Free; Temperature: -55°C+155°C; Tolerance: 1%; Voltage: 50V; Wattage: 1/16W; Weight: 0.8g/1000pcs; Datasheet: Y:\MIS_DATABASE\DATASHEETS\RESISTORS\YAGEO-RC0402.PDF
U47 = TPD6E001RSE_UQFN10: IC 6CH ESD-PROTECTION ARRAY UQFN10; Chkd/date: USMAN/070612; Crtd /date: BAVISH/160811; Custom_Duty: 15%; Customs_HS_Code: 85423100; Distributor_name: DIGIKEY; Distributor_part_number: 296-21888-1-ND; Footprint Path: Y:\MIS_DATABASE\Library\ALTIUM_TOOL\PCB_FOOTPRINTS\Altium_Footprint_Lib.PcbLib; Height: 0.60MM; IBISSP_MODLES: Y:\MIS_DATABASE\IBIS\ICs\INTERFACE\TPD6E001RSE.IBS; Library Path: Y:\MIS_DATABASE\Library\ALTIUM_TOOL\SCHEMATICS_PARTS\MS_MISCINTERFACE_Library.schlib; Mfr_name: TEXAS INSTRUMENTS; Mistral Part No: 141011080020-R; Package: UQFN10; Part_type: ICS\INTERFACE; Project: DM385EVM_BASE-BOARD; RoHS: RoHS; Temperature: -40°C+85°C; Tolerance: NA; Voltage: NA; Wattage: NA; Weight: 7mg; Datasheet: Y:\MIS_DATABASE\DATASHEETS\ICS\INTERFACE\TPD6E001.PDF
U28 U48 U74 U116 = SN74LVC1G08DBVR_SOT23-5: IC SINGLE 2-INPUT POSITIVE AND GATE SOT23-5; Chkd/date: SHREESHAIL/270906; Crtd /date: MAZHAR/270906; Custom_Duty: 15%; Customs_HS_Code: 85423100; Distributor_name: DIGIKEY; Distributor_part_number: 296-11601-1-ND; Height: 1.45MM; Mfr_name: TEXAS INSTRUMENTS; Mistral Part No: 141009030228-R; Part_type: ICS\DIGITAL\GATES; Project: SVDO_RMB_MMA; RoHS: Sb/ Br FREE; Datasheet: Y:\MIS_DATABASE\DATASHEETS\ICS\DIGITAL\GATES\SN74LVC1G08.PDF
U51 = MTFC16GAPALBH_TFBGA153: IC 16GB e-MMC MEMORY TFBGA153; Chkd/date: MANIRAJA/070220; Crtd /date: ALVY/070220; Custom_Duty: 15%; Customs_HS_Code: 85423100; Distributor_name: DIGIKEY; Distributor_part_number: MTFC16GAPALBH-IT-ND; Footprint Path: Y:\MIS_DATABASE\Library\ALTIUM_TOOL\PCB_FOOTPRINTS\Altium_Footprint_Lib.PcbLib; Height: 1.10MM; Library Path: Y:\MIS_DATABASE\Library\ALTIUM_TOOL\SCHEMATICS_PARTS\MS_MISCMEMORY_Library.schlib; Mfr_name: MICRON; Mistral Part No: 141120020001-R; Package: TFBGA153; Part_type: ICS\DIGITAL\MEMORY; Project: TI_MAXIE_CPB; RoHS: RoHS; Temperature: -40°C+85°C; Tolerance: NA; Voltage: NA; Wattage: NA; Weight: NA; Datasheet: Y:\MIS_DATABASE\DATASHEETS\ICS\MEMORY\MTFCXX-IT.PDF
U115 = TPS2051BD_SOIC8: IC POWER DISTRIBUTION SWITCH SOIC8; Chkd/date: NAVEED/150714; Crtd /date: VASANTHA/190614; Custom_Duty: 15%; Customs_HS_Code: 85423100; Distributor_name: DIGIKEY; Distributor_part_number: 296-26911-5-ND; Footprint Path: Y:\MIS_DATABASE\Library\ALTIUM_TOOL\PCB_FOOTPRINTS\Altium_Footprint_Lib.PcbLib; Height: 1.75MM; Library Path: Y:\MIS_DATABASE\Library\ALTIUM_TOOL\SCHEMATICS_PARTS\MS_MISCPOWER_Library.schlib; Mfr_name: TEXAS INSTRUMENTS; Mistral Part No: 142014060011-R; Package: SOIC8; Part_type: ICS\POWER; Project: AEGIS_POM; RoHS: RoHS; Temperature: -40°C+125°C; Tolerance: NA; Voltage: NA; Wattage: NA; Weight: 72.6mg; Datasheet: Y:\MIS_DATABASE\DATASHEETS\MISC\REGULATORS\TPS2051BDBVR.PDF
R136 R398 = RESISTOR: RES 100K 1/16W 5% 0402; Chkd/date: VASANTHA/061216; Crtd /date: BAVISH/010611; Custom_Duty: 15%; Customs_HS_Code: 85332119; Distributor_name: DIGIKEY; Distributor_part_number: 541-100KJCT-ND; Height: 0.40MM; Mfr_name: VISHAY; Mfr_part_number: CRCW0402100KJNED; Mistral Part No: 110011060002-R; Package: 0402; Part_type: RESISTORS\FIXED; Project: AM4515_EVM_LCD; RoHS: RoHS; Temperature: -55°C+155°C; Tolerance: 5%; Voltage: NA; Wattage: 1/16W; Weight: 0.65mg; Datasheet: Y:\MIS_DATABASE\DATASHEETS\RESISTORS\CRCW0603.PDF
R706 = RESISTOR: RES 10E 1/16W 1% 0402; Chkd/date: MANIRAJA/070218; Crtd /date: ALVY/070218; Custom_Duty: 15%; Customs_HS_Code: 85332119; Distributor_name: DIGIKEY; Distributor_part_number: 311-10.0LRCT-ND; Height: 0.40MM; Mfr_name: YAGEO AMERICA; Mfr_part_number: RC0402FR-0710RL; Mistral Part No: 110018020004-R; Package: 0402; Part_type: RESISTORS\FIXED; Project: TI_MAXIE_CPB; RoHS: RoHS; Temperature: -55°C+155°C; Tolerance: 1%; Voltage: NA; Wattage: 1/16W; Weight: 0.65mg; Datasheet: Y:\MIS_DATABASE\DATASHEETS\RESISTORS\YAGEO-RC0402.PDF
RA8 = RESARR_ISO8: RES ARRAY 22E 62.5mW 5% 0402; Chkd/date: MAZHAR/040809; Crtd /date: USMAN/040908; Distributor_name: DIGIKEY; Distributor_part_number: 741X163220JPCT-ND; Height: 0.55MM; Mfr_name: CTS; Mfr_part_number: 741X163220JP; Mistral Part No: 110009030020-R; Package: 0402; Part_type: RESISTORS\ARRAY; Project: CPB; RoHS: RoHS; SIGNAL_MODEL: RESARR_ISO8_RESA_0402-8_22E_22E; Tolerance: 5%; Wattage: 63mW; Datasheet: Y:\MIS_DATABASE\DATASHEETS\RESISTORS\741-6SER.PDF
U24 = MT25QL02GCBB8E12_TPBGA24: IC 128Mb SERIAL NOR FLASH MEMORY TPBGA24; Chkd/date: MANIRAJA/110917; Crtd /date: MANIRAJA/110917; Custom_Duty: 15%; Customs_HS_Code: 85423100; Distributor_name: DIGIKEY; Distributor_part_number: MT25QL128ABA8E12-0SIT-ND; Height: 1.20MM; Mfr_name: MICRON; Mfr_part_number: MT25QL128ABA8E12-0SIT; Mistral Part No: 141117090006-R; Package: TPBGA24; Part_type: ICS\DIGITAL\MEMORY; Project: TI_SVB_MAXWELL_FMB; RoHS: RoHS; Temperature: -40°C+85°C; Tolerance: NA; Voltage: NA; Wattage: NA; Weight: NA; Datasheet: Y:\MIS_DATABASE\DATASHEETS\ICS\MEMORY\MT25QLXXX.PDF
U77 = MT35XU512ABA1G12_TPBGA24: IC 1.7-2V 512Mb AUTOMOTIVE XCCELA FLASH MEMORY TPBGA24; Chkd/date: MANIRAJA/030719; Crtd /date: MANIRAJA/030719; Custom_Duty: 15%; Customs_HS_Code: 85423100; Distributor_name: DIGIKEY; Distributor_part_number: MT35XU512ABA1G12-0AAT-ND; Footprint Path: Y:\MIS_DATABASE\Library\ALTIUM_TOOL\PCB_FOOTPRINTS\Altium_Footprint_Lib.PcbLib; Height: 1.20MM; Library Path: Y:\MIS_DATABASE\Library\ALTIUM_TOOL\SCHEMATICS_PARTS\MS_MISCMEMORY_Library.schlib; Mfr_name: MICRON; Mistral Part No: 141119070001-R; Package: TPBGA24; Part_type: ICS\DIGITAL\MEMORY; Project: TI_MAXIE_CPB; RoHS: RoHS; Temperature: -40°C+105°C; Tolerance: NA; Voltage: NA; Wattage: NA; Weight: NA; Datasheet: Y:\MIS_DATABASE\DATASHEETS\ICS\MEMORY\MT35XU5XX.PDF
U34 = AM654X_BGA784: IC AM65X MICRO CONTROLLER UNIT BGA784; Chkd/date: MANIRAJA/310120; Crtd /date: MANIRAJA/310120; Custom_Duty: 15%; Customs_HS_Code: 85423100; Distributor_name: NA; Distributor_part_number: NA; Footprint Path: Y:\MIS_DATABASE\Library\ALTIUM_TOOL\PCB_FOOTPRINTS\Altium_Footprint_Lib.PcbLib; Height: 1.63MM; Library Path: Y:\MIS_DATABASE\Library\ALTIUM_TOOL\SCHEMATICS_PARTS\MS_MICROCONTROLLER_Library.schlib; Mfr_name: TEXAS INSTRUMENTS; Mistral Part No: 141220010002; Package: BGA784; Part_type: ICS\DIGITAL\MICROCONTROLLER; Project: TI_MAXIE_CPB; RoHS: NA; Temperature: NA; Tolerance: NA; Voltage: NA; Wattage: NA; Weight: NA; Datasheet: Y:\MIS_DATABASE\DATASHEETS\ICS\DIGITAL\MICROCONTROLLER\MAXWELLM4.PDF

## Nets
DGND: C30.2 C31.2 C32.2 C33.2 C34.2 C35.2 C36.2 C52.2 C57.2 C64.2 C65.2 C67.2 C70.2 C71.2 C121.2 C122.2 C133.2 C181.2 C182.2 C183.2 C184.2 C185.2 C190.2 C202.2 C203.2 C204.2 C205.2 C206.2 C207.2 C230.2 C233.2 C235.2 C328.2 C334.2 C346.2 C362.2 C504.2 C505.2 C579.2 C583.2 C585.2 C593.2 C594.2 C597.2 C617.2 C618.2 C620.2 C622.2 C623.2 C625.2 C692.2 C693.2 C695.2 C696.2 C697.2 J17.3(VSS1) J17.6(VSS2) J17.G2 J17.G4 J17.G5 R136.2 R186.2 R212.2 R219.1 R252.1 R398.2 R462.1 R535.2 R536.2 R730.2 R731.2 R739.2 R740.2 R799.1 U24.B3(VSS) U28.3(GND) U38.A2(VSSQ) U38.A8(VSSQ) U38.A9(VSS) U38.C8(VSS) U38.D1(VSSQ) U38.D9(VSSQ) U38.E1(VSS) U38.E9(VSS) U38.G1(VSS) U38.H9(VSS) U38.K1(VSS) U38.K9(VSS) U38.N1(VSS) U47.5(GND) U48.3(GND) U51.A6(VSS) U51.C4(VSSQ) U51.E7(VSS) U51.G5(VSS) U51.H10(VSS) U51.J5(VSS) U51.K8(VSS) U51.N2(VSSQ) U51.N5(VSSQ) U51.P4(VSSQ) U51.P6(VSSQ) U74.3(GND) U77.B3(VSS) U77.C1(VSS) U77.E5(VSS) U115.1(GND) U116.3(GND) ; also on sheet 11 12 13 14 15 16 20 21 22 23 24 25 26 27 28 29 30 31 32 33 34 35 36 37 38 39 40 41 42 43 44
VCC1V8: C230.1 C334.1 C346.1 C362.1 C617.1 C625.1 R33.2 R262.1 R263.1 R264.1 R265.1 R266.1 R267.1 R268.1 R269.1 R288.2 R385.2 R402.2 R403.2 R406.2 R411.2 R420.2 R421.2 R422.2 R423.2 R424.2 R625.1 R732.2 R795.1 U48.5(VCC) U51.C6(VCCQ) U51.M4(VCCQ) U51.N4(VCCQ) U51.P3(VCCQ) U51.P5(VCCQ) U74.5(VCC) U77.B4(VCC) U77.D1(VCC) U77.E4(VCC) ; also on sheet 11 20 21 22 23 26 29 31 33 35 36 37 38 41 44
VCC3V3_IO: C121.1 C122.1 C133.1 C622.1 C623.1 C693.1 C696.1 C697.1 R123.2 R124.2 R126.2 R127.2 R133.2 R153.2 R159.2 R303.2 R390.2 R736.1 R747.2 R748.2 U24.B4(VCC) U28.5(VCC) U51.E6(VCC) U51.F5(VCC) U51.J10(VCC) U51.K9(VCC) U115.2(IN1) U115.3(IN2) U116.5(VCC) ; also on sheet 11 20 21 22 23 24 25 26 28 29 30 31 33 34 35 36 37 38 39 41 42 43 44
VCC_2V5: FL1.1 ; also on sheet 35 42
VDD_DDR4: C182.1 C183.1 C185.1 C190.1 C202.1 C204.1 C205.1 C207.1 C303.1 C579.1 C583.1 C585.1 C593.1 C594.1 R182.2 R220.2 R460.2 R503.2 R516.1 U38.A1(VDD) U38.B2(VDDQ) U38.B8(VDDQ) U38.C1(VDDQ) U38.C7(VDD) U38.C9(VDDQ) U38.E2(VDDQ) U38.E8(VDDQ) U38.F1(VDD) U38.F9(VDD) U38.H1(VDD) U38.J9(VDD) U38.M1(VDD) U38.N9(VDD) ; also on sheet 16 26 42
VDD_MMC1: C692.1 C695.1 FL38.1 U115.6(OUT1) U115.7(OUT2) U115.8(OUT3) ; also on sheet 13
VDD_MMC1_SD: C235.1 FL38.2 J17.4(VDD)
VDDIM: C618.1 C620.1 U51.C2(VDDIM)
VDDR_VTT: C30.1 C31.1 C32.1 C33.1 C34.1 C35.1 C36.1 C52.1 C57.1 C64.1 C65.1 C67.1 C70.1 C71.1 C328.1 R43.2 R44.2 R45.2 R46.2 R47.2 R48.2 R49.2 R56.2 R57.2 R61.2 R63.2 R67.2 R69.2 R70.2 R366.2 R367.2 R368.2 R369.2 R370.2 R371.2 R372.2 R377.2 R379.2 R382.2 R383.2 R386.2 R389.2 R391.2 R393.2 R742.2 ; also on sheet 42
VDDSHV_SD_IO: C233.1 R606.1 R607.1 R608.1 R614.1 R616.1 TP75.1(TP) U47.10(VCC) ; also on sheet 12 13 14
DDR_A0: R389.1 U34.A10(DDR_AC0) U38.L3(A0) ; also on sheet 16
DDR_A1: R43.1 U34.D9(DDR_AC1) U38.L7(A1) ; also on sheet 16
DDR_A2: R393.1 U34.C9(DDR_AC2) U38.M3(A2) ; also on sheet 16
DDR_A3: R369.1 U34.E9(DDR_AC3) U38.K7(A3) ; also on sheet 16
DDR_A4: R386.1 U34.A9(DDR_AC4) U38.K3(A4) ; also on sheet 16
DDR_A5: R368.1 U34.E8(DDR_AC5) U38.L8(A5) ; also on sheet 16
DDR_A6: R67.1 U34.F8(DDR_AC6) U38.L2(A6) ; also on sheet 16
DDR_A7: R49.1 U34.C7(DDR_AC7) U38.M8(A7) ; also on sheet 16
DDR_A8: R69.1 U34.C8(DDR_AC8) U38.M2(A8) ; also on sheet 16
DDR_A9: R367.1 U34.D7(DDR_AC9) U38.M7(A9) ; also on sheet 16
DDR_A10: R383.1 U34.E7(DDR_AC10) U38.J3(A10/AP) ; also on sheet 16
DDR_A11: R70.1 U34.A6(DDR_AC11) U38.N2(A11) ; also on sheet 16
DDR_A12: R370.1 U34.F7(DDR_AC12) U38.J7(A12/BC_N) ; also on sheet 16
DDR_A13: R44.1 U34.D6(DDR_AC13) U38.N8(A13) ; also on sheet 16
DDR_A14_WEn: R382.1 U34.C6(DDR_AC14) U38.H2(WE_N/A14) ; also on sheet 16
DDR_A15_CAS: R46.1 U34.F6(DDR_AC15) U38.H7(CAS_N/A15) ; also on sheet 16
DDR_A16_RAS: R371.1 U34.E6(DDR_AC16) U38.H8(RAS_N/A16) ; also on sheet 16
DDR_A17: R366.1 U34.E5(DDR_AC17) U38.N7(A17/NF) ; also on sheet 16
DDR_ACTn: R742.1 U34.D8(DDR_AC18) U38.H3(ACT_N) ; also on sheet 16
DDR_ALERTn: R460.1 U34.D5(DDR_ALERTn) U38.L9(ALERT_N) ; also on sheet 16
DDR_BA0: R63.1 U34.D10(DDR_AC19) U38.K2(BA0) ; also on sheet 16
DDR_BA1: R48.1 U34.E10(DDR_AC20) U38.K8(BA1) ; also on sheet 16
DDR_BG0: R61.1 U34.C10(DDR_AC21) U38.J2(BG0) ; also on sheet 16
DDR_BG1: R47.1 U34.F11(DDR_AC22) U38.J8(BG1) ; also on sheet 16
DDR_CKE: R57.1 R731.1 U34.C11(DDR_AC26) U38.G3(CKE) ; also on sheet 16
DDR_CKE1: R379.1 R730.1 U34.D12(DDR_AC29) U38.G2(C0/CKE1) ; also on sheet 16
DDR_CLKN: R374.1 U34.B8(DDR_CK0N) U38.F8(CK_C) ; also on sheet 16
DDR_CLKP: R373.1 U34.A8(DDR_CK0P) U38.F7(CK_T) ; also on sheet 16
DDR_CS1n: R45.1 U34.E11(DDR_AC27) U38.G8(C1/CS1_N) ; also on sheet 16
DDR_CSn: R372.1 U34.D11(DDR_AC24) U38.G7(CS_N) ; also on sheet 16
DDR_DM0: U34.E1(DDR_DM0) ; also on sheet 16
DDR_DM1: U34.C5(DDR_DM1) ; also on sheet 16
DDR_DM2: U34.D14(DDR_DM2) ; also on sheet 16
DDR_DM3: U34.B17(DDR_DM3) ; also on sheet 16
DDR_DM4: U34.C17(DDR_ECC_DM) U38.A7(NF/NF/DM_N/DBI_N/TDQS_T)
DDR_DQ0: U34.A3(DDR_DQ0) ; also on sheet 16
DDR_DQ1: U34.B2(DDR_DQ1) ; also on sheet 16
DDR_DQ2: U34.C2(DDR_DQ2) ; also on sheet 16
DDR_DQ3: U34.D2(DDR_DQ3) ; also on sheet 16
DDR_DQ4: U34.E2(DDR_DQ4) ; also on sheet 16
DDR_DQ5: U34.G1(DDR_DQ5) ; also on sheet 16
DDR_DQ6: U34.F2(DDR_DQ6) ; also on sheet 16
DDR_DQ7: U34.F1(DDR_DQ7) ; also on sheet 16
DDR_DQ8: U34.E3(DDR_DQ8) ; also on sheet 16
DDR_DQ9: U34.C3(DDR_DQ9) ; also on sheet 16
DDR_DQ10: U34.D3(DDR_DQ10) ; also on sheet 16
DDR_DQ11: U34.B3(DDR_DQ11) ; also on sheet 16
DDR_DQ12: U34.D4(DDR_DQ12) ; also on sheet 16
DDR_DQ13: U34.C4(DDR_DQ13) ; also on sheet 16
DDR_DQ14: U34.B4(DDR_DQ14) ; also on sheet 16
DDR_DQ15: U34.B5(DDR_DQ15) ; also on sheet 16
DDR_DQ16: U34.E13(DDR_DQ16) ; also on sheet 16
DDR_DQ17: U34.C14(DDR_DQ17) ; also on sheet 16
DDR_DQ18: U34.B14(DDR_DQ18) ; also on sheet 16
DDR_DQ19: U34.A14(DDR_DQ19) ; also on sheet 16
DDR_DQ20: U34.E14(DDR_DQ20) ; also on sheet 16
DDR_DQ21: U34.B13(DDR_DQ21) ; also on sheet 16
DDR_DQ22: U34.C13(DDR_DQ22) ; also on sheet 16
DDR_DQ23: U34.D13(DDR_DQ23) ; also on sheet 16
DDR_DQ24: U34.D15(DDR_DQ24) ; also on sheet 16
DDR_DQ25: U34.C15(DDR_DQ25) ; also on sheet 16
DDR_DQ26: U34.E16(DDR_DQ26) ; also on sheet 16
DDR_DQ27: U34.E15(DDR_DQ27) ; also on sheet 16
DDR_DQ28: U34.D16(DDR_DQ28) ; also on sheet 16
DDR_DQ29: U34.B16(DDR_DQ29) ; also on sheet 16
DDR_DQ30: U34.C16(DDR_DQ30) ; also on sheet 16
DDR_DQ31: U34.A17(DDR_DQ31) ; also on sheet 16
DDR_DQ36: U34.B19(DDR_ECC_D0) U38.C2(DQ0)
DDR_DQ37: U34.B18(DDR_ECC_D1) U38.B7(DQ1)
DDR_DQ38: U34.C18(DDR_ECC_D2) U38.D3(DQ2)
DDR_DQ39: U34.D18(DDR_ECC_D3) U38.D7(DQ3)
DDR_DQ40: U34.E18(DDR_ECC_D4) U38.D2(DQ4/NC)
DDR_DQ41: U34.E17(DDR_ECC_D5) U38.D8(DQ5/NC)
DDR_DQ42: U34.D17(DDR_ECC_D6) U38.E3(DQ6/NC)
DDR_DQS0_N: U34.C1(DDR_DQS0N) ; also on sheet 16
DDR_DQS0_P: U34.D1(DDR_DQS0P) ; also on sheet 16
DDR_DQS1_N: U34.A4(DDR_DQS1N) ; also on sheet 16
DDR_DQS1_P: U34.A5(DDR_DQS1P) ; also on sheet 16
DDR_DQS2_N: U34.A12(DDR_DQS2N) ; also on sheet 16
DDR_DQS2_P: U34.A13(DDR_DQS2P) ; also on sheet 16
DDR_DQS3_N: U34.A16(DDR_DQS3N) ; also on sheet 16
DDR_DQS3_P: U34.A15(DDR_DQS3P) ; also on sheet 16
DDR_DQS_N: U34.A18(DDR_ECC_DQSN) U38.B3(DQS_C)
DDR_DQS_P: U34.A19(DDR_ECC_DQSP) U38.C3(DQS_T)
DDR_ODT: R377.1 U34.B11(DDR_AC25) U38.F3(ODT) ; also on sheet 16
DDR_ODT1: R56.1 U34.E12(DDR_AC28) U38.F2(C2/ODT1) ; also on sheet 16
DDR_PARITY: R391.1 U34.B10(DDR_AC23) U38.N3(PAR) ; also on sheet 16
DDR_RESET#: R165.1 R171.1 R219.2 R220.1 U38.L1(RESET_N) ; also on sheet 16
DDR_RESET_FS: R171.2 R182.1 U34.F16(DDR_FS_RESETn)
DDR_TEN: R462.2 R503.1 U38.G9(TEN) ; also on sheet 16
DDR_VPP: C181.1 C184.1 C203.1 FL1.2 U38.B1(VPP) U38.M9(VPP) ; also on sheet 16
DDR_VREFCA: C206.1 C597.1 R728.1 U38.J1(VREFCA) ; also on sheet 16 42
DDR_VTT_EN: U34.P3(MCU_OSPI1_D0) ; also on sheet 37
eMMC_RSTn: R288.1 U48.4(Y) U51.K5(RST_N)
EXP_PCIe_DET_INTn: U34.T1(MCU_OSPI1_CLK) ; also on sheet 20
GPIO_eMMC_RSTn: R303.1 U48.1(A) ; also on sheet 37
GPIO_OSPI_RSTn: R390.1 U74.1(A) ; also on sheet 37
GPIO_SPI0_RSTn: R159.1 U28.1(A) ; also on sheet 37
MCU_ETH1_INTn_SDIO: U34.C24(MMC1_SDWP) ; also on sheet 38
MMC0_CALPAD: R535.1 U34.D24(MMC0_CALPAD)
MMC0_CLK: R532.2 R795.2 U51.M6(CLK)
MMC0_DS: R252.2 R253.2 U51.H5(DS)
MMC0_VCTRL_TP: TP59.1(TP) U34.D23(RSV12)
MMC1_CALPAD: R536.1 U34.F23(MMC1_CALPAD)
MMC1_CLK: J17.5(CLK) R534.1 U47.8(IO6)
MMC1_CLK_R: R534.2 U34.C27(MMC1_CLK)
MMC1_CMD: J17.2(CMD) R616.2 U34.C28(MMC1_CMD) U47.1(IO1)
MMC1_D0: J17.7(DAT0) R607.2 U34.D28(MMC1_DAT0) U47.7(IO5)
MMC1_D1: J17.8(DAT1) R606.2 U34.E27(MMC1_DAT1) U47.6(IO4)
MMC1_D2: J17.9(DAT2) R608.2 U34.D26(MMC1_DAT2) U47.3(IO3)
MMC1_D3: J17.1(CD/DAT3) R614.2 U34.D27(MMC1_DAT3) U47.2(IO2)
MMC1_SD_EN: R747.1 U116.1(A) ; also on sheet 20
MMC1_SD_LS_EN: R748.1 U115.4(EN) U116.4(Y)
MMC1_SDCD: J17.G1 R310.2 U34.B24(MMC1_SDCD)
MMC1_VCTRL_TP: TP61.1(TP) U34.E23(RSV13)
OSPI_CLK: R398.1 R430.2 R706.1
OSPI_CS: R403.1 R429.2 U77.C2(S#)
OSPI_DQ0: R424.1 RA8.4 U77.D3(DQ0)
OSPI_DQ1: R421.1 RA8.7 U77.D2(DQ1)
OSPI_DQ2: R402.1 RA8.1 U77.C4(DQ2/W#)
OSPI_DQ3: R411.1 RA8.3 U77.D4(DQ3)
OSPI_DQ4: R406.1 RA8.2 U77.D5(DQ4)
OSPI_DQ5: R423.1 RA8.5 U77.E3(DQ5)
OSPI_DQ6: R422.1 RA8.6 U77.E2(DQ6)
OSPI_DQ7: R420.1 RA8.8 U77.E1(DQ7)
OSPI_DQS: R410.2 R732.1 R799.2 U34.U2(MCU_OSPI0_DQS)
OSPI_INT: R33.1 R745.1 U34.N2(MCU_OSPI1_CSN0)
OSPI_LBCLKO_GPIO: U34.U1(MCU_OSPI0_LBCLKO) ; also on sheet 35
OSPI_RSTn: R385.1 U74.4(Y) U77.A4(RESET#)
PORz_OUT: U28.2(B) U74.2(B) ; also on sheet 21 25 33 34 35 44
RESETSTATZ: U48.2(B) U116.2(B) ; also on sheet 34
SoC_DDR_VREFCA: C504.1 C505.1 R728.2 U34.F12(DDR_VREF0)
SOC_DVDD1V8: R310.1 R741.1 ; also on sheet 13 14 26 38
SOC_MCU_UART1_CTS_1V8: U34.P1(MCU_OSPI1_D3) ; also on sheet 31
SOC_MCU_UART1_RTS_1V8: U34.N3(MCU_OSPI1_CSN1) ; also on sheet 31
SOC_MCU_UART1_RX_1V8: U34.P4(MCU_OSPI1_D1) ; also on sheet 31
SOC_MCU_UART1_TX_1V8: U34.P5(MCU_OSPI1_D2) ; also on sheet 31
SoC_MMC0_CD: R739.1 U34.A23(MMC0_SDCD)
SoC_MMC0_CLK: R532.1 U34.B25(MMC0_CLK)
SoC_MMC0_CMD: R625.2 U34.B27(MMC0_CMD) U51.M5(CMD)
SoC_MMC0_DAT0: R264.2 U34.A26(MMC0_DAT0) U51.A3(DAT0)
SoC_MMC0_DAT1: R265.2 U34.E25(MMC0_DAT1) U51.A4(DAT1)
SoC_MMC0_DAT2: R267.2 U34.C26(MMC0_DAT2) U51.A5(DAT2)
SoC_MMC0_DAT3: R262.2 U34.A25(MMC0_DAT3) U51.B2(DAT3)
SoC_MMC0_DAT4: R263.2 U34.E24(MMC0_DAT4) U51.B3(DAT4)
SoC_MMC0_DAT5: R266.2 U34.A24(MMC0_DAT5) U51.B4(DAT5)
SoC_MMC0_DAT6: R268.2 U34.B26(MMC0_DAT6) U51.B5(DAT6)
SoC_MMC0_DAT7: R269.2 U34.D25(MMC0_DAT7) U51.B6(DAT7)
SoC_MMC0_DS: R253.1 U34.C25(MMC0_DS)
SoC_MMC0_WP: R740.1 R741.2 U34.B23(MMC0_SDWP)
SoC_OSPI_CLK: R430.1 U34.V1(MCU_OSPI0_CLK)
SoC_OSPI_DQ0: RA8.13 U34.U4(MCU_OSPI0_D0)
SoC_OSPI_DQ1: RA8.10 U34.U5(MCU_OSPI0_D1)
SoC_OSPI_DQ2: RA8.16 U34.T2(MCU_OSPI0_D2)
SoC_OSPI_DQ3: RA8.14 U34.T3(MCU_OSPI0_D3)
SoC_OSPI_DQ4: RA8.15 U34.T4(MCU_OSPI0_D4)
SoC_OSPI_DQ5: RA8.12 U34.T5(MCU_OSPI0_D5)
SoC_OSPI_DQ6: RA8.11 U34.R2(MCU_OSPI0_D6)
SoC_OSPI_DQ7: RA8.9 U34.R3(MCU_OSPI0_D7)
SOC_SPI0_CLK: R136.1 U24.B2(C) ; also on sheet 33 34
SOC_SPI0_CS0: R133.1 U24.C2(S#) ; also on sheet 34
SOC_SPI0_D0: R123.1 U24.D3(DQ0) ; also on sheet 33 34
SOC_SPI0_D1: R126.1 U24.D2(DQ1) ; also on sheet 33 34
SPI0_RSTn: R153.1 U24.A4(RESET#/DNU) U28.4(Y)
SPI0_WP: R127.1 U24.C4(W#/DQ2)
VPP: U77.C5(VPP)
VPP_LDO_EN: U34.R1(MCU_OSPI1_LBCLKO) ; also on sheet 41
WKUP_GPIO0_13_INTn: U34.R5(MCU_OSPI0_CSN1) ; also on sheet 11
WKUP_GPIO0_27_INTn: U34.P2(MCU_OSPI1_DQS) ; also on sheet 11
N15352717: R410.1 U77.C3(DQS)
N15820521: R516.2 U38.E7(DQ7/NC)
N15820751: TP18.1(TP) U38.A3(NF/NF/TDQS_C/NF)
N15820885: R212.1 U38.B9(ZQ)
N17817176: TP41.1(TP) U34.A7(DDR_CK1P)
N17817178: TP39.1(TP) U34.B7(DDR_CK1N)
N17817198: TP45.1(TP) U34.C12(RSV5)
N17817246: TP42.1(TP) U34.F9(RSV6)
N17817413: R186.1 U34.F13(DDR_VTP)
N17817732: TP44.1(TP) U34.F10(RSV7)
N17818942: TP46.1(TP) U34.F15(DDR_VREF_ZQ)
N18948512: R124.1 U24.D4(DQ3)
N18950218: R429.1 U34.R4(MCU_OSPI0_CSN0)
N19311007: R165.2 U34.A11(DDR_RESETn)
N20584902: R706.2 U77.B2(C)
N20753582: C303.2 R373.2 R374.2
N22464359: R736.2 U115.5(~{OC})
N22573349: R745.2 U77.A5(DNU1)

Not connected (* = marked no-connect by the designer): J17 G3*; U24 A2(DNU1)* A3(DNU2)* A5(DNU3)* B1(DNU4)* B5(DNU5)* C1(DNU6)* C3(DNU7)* C5(DNU8)* D1(DNU9)* D5(DNU10)* E1(DNU11)* E2(DNU12)* E3(DNU13)* E4(DNU14)* E5(DNU15)*; U47 4(NC1)* 9(NC2)*; U51 A1(NC1) A2(NC2) A7(RFU1) A8(NC3) A9(NC4) A10(NC5) A11(NC6) A12(NC7) A13(NC8) A14(NC9) B1(NC10) B7(NC11) B8(NC12) B9(NC13) B10(NC14) B11(NC15) B12(NC16) B13(NC17) B14(NC18) C1(NC19) C3(NC20) C5(NC21) C7(NC22) C8(NC23) C9(NC24) C10(NC25) C11(NC26) C12(NC27) C13(NC28) C14(NC29) D1(NC30) D2(NC31) D3(NC32) D4(NC33) D12(NC34) D13(NC35) D14(NC36) E1(NC37) E2(NC38) E3(NC39) E5(RFU2) E8(VSF1) E9(VSF2) E10(VSF3) E12(NC40) E13(NC41) E14(NC42) F1(NC43) F2(NC44) F3(NC45) F10(VSF4) F12(NC46) F13(NC47) F14(NC48) G1(NC49) G2(NC50) G3(NC51) G10(VSF5) G12(NC52) G13(NC53) G14(NC54) H1(NC55) H2(NC56) H3(NC57) H12(NC58) H13(NC59) H14(NC60) J1(NC61) J2(NC62) J3(NC63) J12(NC64) J13(NC65) J14(NC66) K1(NC67) K2(NC68) K3(NC69) K6(RFU3) K7(RFU4) K10(VSF6) K12(NC70) K13(NC71) K14(NC72) L1(NC73) L2(NC74) L3(NC75) L12(NC76) L13(NC77) L14(NC78) M1(NC79) M2(NC80) M3(NC81) M7(NC82) M8(NC83) M9(NC84) M10(NC85) M11(NC86) M12(NC87) M13(NC88) M14(NC89) N1(NC90) N3(NC91) N6(NC92) N7(NC93) N8(NC94) N9(NC95) N10(NC96) N11(NC97) N12(NC98) N13(NC99) N14(NC100) P1(NC101) P2(NC102) P7(NC103) P8(NC104) P9(NC105) P10(VSF7) P11(NC106) P12(NC107) P13(NC108) P14(NC109); U77 A2(RFU1)* A3(RFU2)* B1(RFU3)* B5(DNU2)*

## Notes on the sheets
sheet 17
- SoC DDR INTERFACE
- ECC DEVICE
- DDR TERMINATION
sheet 18
- eMMC FLASH
- eMMC FLASH RESET
- SD CARD INTERFACE
sheet 19
- SOC OSPI INTERFACE
- SPI NOR Flash
- OSPI  FLASH
- SPI FLASH RESET
- OSPI FLASH RESET
